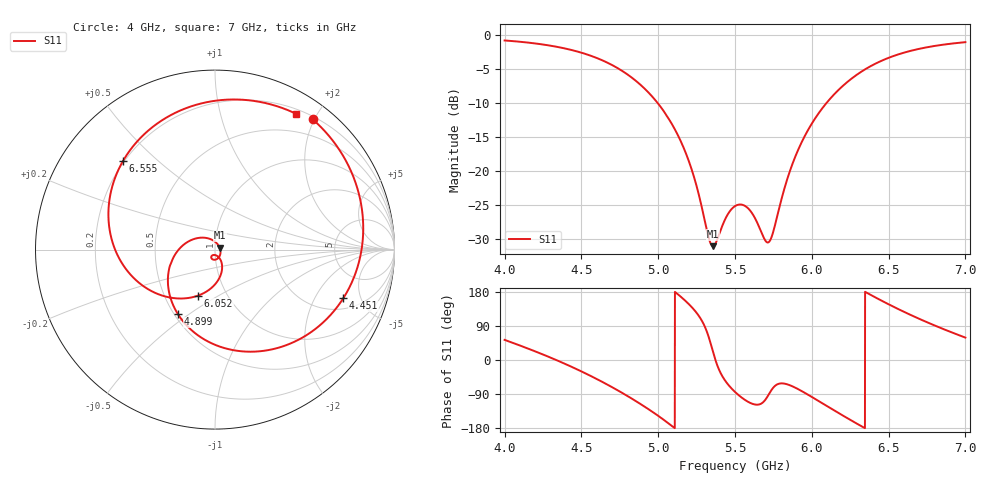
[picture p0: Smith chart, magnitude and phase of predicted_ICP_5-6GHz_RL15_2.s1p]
! ICP-predicted S11, target 5.000-6.000 GHz at -15 dB. Complex ensemble mean (passive and causal);
! its |S11| can differ slightly from the dB-domain mean reported in designs.csv.
!  Air_gap = 2.69mm
!  W_Patch = 12.55mm
!  L_Patch = 18.03mm
!  Sx = 0.78mm
!  Sy = 1.92mm
!  W_Patch1 = 10.84mm
!  WS = 0.86mm
!  Curve_Amp1 = 0.73mm
!  Extra = 4.65mm
# GHz S MA R 50
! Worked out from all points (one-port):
!   3001 points, 4 GHz to 7 GHz, reference 50 ohm
!   lowest |S11| = -31.0 dB at 5.356 GHz (marker M1), VSWR 1.06, Z = 52.7 + j1.14 ohm
!   |S11| at or under -10 dB: 4.996 GHz to 6.096 GHz (1.1 GHz wide, 19.8 % of centre)
!   S11 on the Smith chart (normalised r, x): 4 GHz: 0.24, +1.98; 4.451 GHz: 2.69, -3.50; 4.899 GHz: 0.52, -0.45; 6.052 GHz: 0.73, -0.41; 6.555 GHz: 0.19, +0.39; 7 GHz: 0.26, +1.74
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4  0.9071 53.1
4.202  0.8618 22.3
4.375  0.8004 -6.9
4.451  0.7645 -20.8
4.609  0.6683 -52.1
4.75  0.5563 -83.2
4.899  0.4149 -119.8
5.006  0.3058 -149.0
5.125  0.1863 174.5
5.22  0.1011 138.8
5.328  0.03271 61.7
5.356  0.02817 22.6
5.449  0.04737 -61.7
5.5  0.05538 -84.2
5.589  0.05284 -111.2
5.694  0.03141 -106.8
5.72  0.03017 -90.8
5.747  0.03529 -74.0
5.875  0.1136 -69.7
6.052  0.2727 -110.1
6.153  0.3728 -134.8
6.25  0.468 -157.9
6.406  0.6066 166.9
6.555  0.7121 136.0
6.625  0.7518 122.4
6.717  0.7952 105.5
6.807  0.8293 89.9
7  0.8813 59.1
